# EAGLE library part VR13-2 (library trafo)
TRANSFORMER 1 primary winding, 2 secondary windings, mounting holes BLOCK

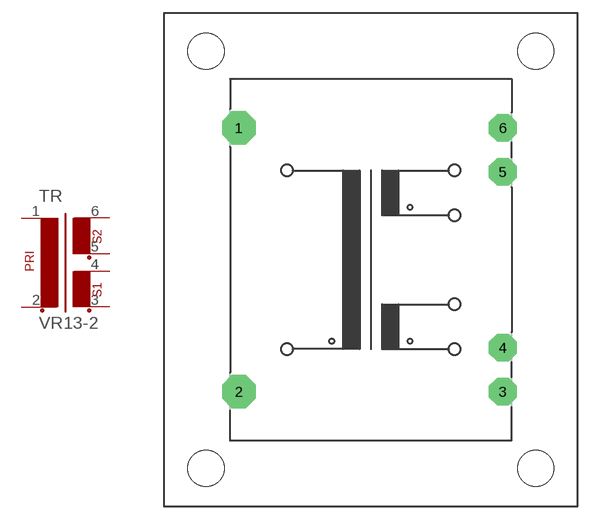
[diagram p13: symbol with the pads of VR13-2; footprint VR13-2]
Designator prefix TR

## VR13-2  [VR13-2]
1  1  pas
2  2  pas
3  3  pas
4  4  pas
5  5  pas
6  6  pas

## Footprint VR13-2 (pad centres in mm)
TRANSFORMER 1 primary winding, 2 secondary windings, mounting holes
drill 1.397 pad 3.81 octagon: 1 -15.011,15.011; 2 -15.011,-15.011
drill 1.397 pad 3.175 octagon: 3 15.011,-15.011; 4 15.011,-10.008; 5 15.011,10.008; 6 15.011,15.011
hole 4.115 at -18.745,-23.749
hole 4.115 at 18.745,-23.749
hole 4.115 at 18.745,23.749
hole 4.115 at -18.745,23.749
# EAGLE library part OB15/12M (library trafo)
TRANSFORMER 2 primary winding, 2 secondary windings with tap, mounting holes BLOCK

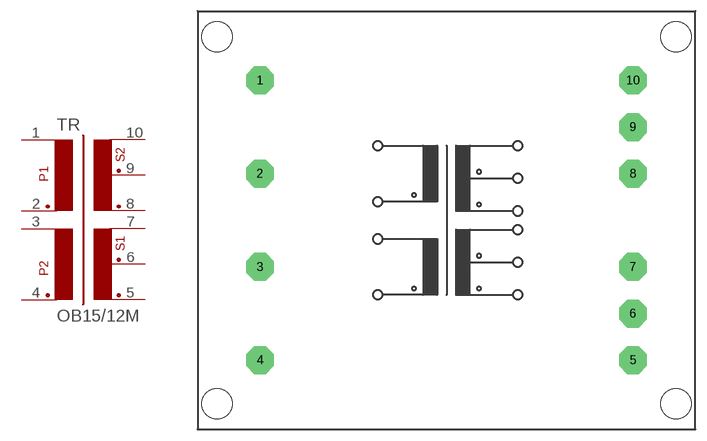
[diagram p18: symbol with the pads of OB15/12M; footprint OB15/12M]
Designator prefix TR

## OB15/12M  [OB15/12M]
1  1  pas
2  2  pas
3  3  pas
4  4  pas
5  5  pas
6  6  pas
7  7  pas
8  8  pas
9  9  pas
10  10  pas

## Footprint OB15/12M (pad centres in mm)
TRANSFORMER 2 primary winding, 2 secondary windings with tap, mounting holes
drill 1.194 pad 3.81 octagon: 1 -25.4,19.05; 2 -25.4,6.35; 3 -25.4,-6.35; 4 -25.4,-19.05; 5 25.4,-19.05; 6 25.4,-12.7; 7 25.4,-6.35; 8 25.4,6.35; 9 25.4,12.7; 10 25.4,19.05
hole 4.115 at -31.267,24.994
hole 4.115 at 31.267,24.994
hole 4.115 at 31.267,-24.994
hole 4.115 at -31.267,-24.994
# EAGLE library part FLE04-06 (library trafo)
TRANSFORMER 2 primary winding, temp. protection fuse, 2 secondary windings, mounting holes BLOCK

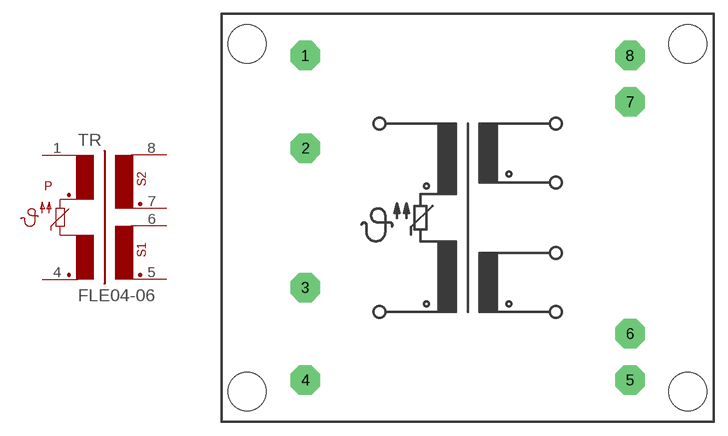
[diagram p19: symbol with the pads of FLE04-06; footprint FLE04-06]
Designator prefix TR

## FLE04-06  [FLE04-06]
1  1  pas
4  4  pas
5  5  pas
6  6  pas
7  7  pas
8  8  pas

## Footprint FLE04-06 (pad centres in mm)
TRANSFORMER 2 primary winding, 2 secondary windings, temp. protection fuse, mounting holes
drill 1.194 pad 3.175 octagon: 1 -17.501,17.501; 2 -17.501,7.518; 3 -17.501,-7.518; 4 -17.501,-17.501; 5 17.501,-17.501; 6 17.501,-12.497; 7 17.501,12.497; 8 17.501,17.501
hole 4.115 at 23.749,18.745
hole 4.115 at 23.749,-18.745
hole 4.115 at -23.774,-18.745
hole 4.115 at -23.774,18.745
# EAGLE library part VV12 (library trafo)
TRANSFORMER 1 primary winding, 2 secondary windings BLOCK

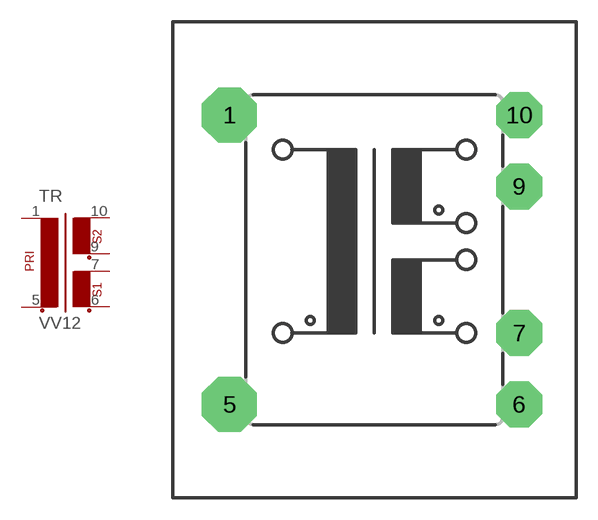
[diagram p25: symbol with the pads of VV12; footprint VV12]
Designator prefix TR

## VV12  [VV12]
1  1  pas
5  2  pas
6  3  pas
7  4  pas
9  5  pas
10  6  pas

## Footprint VV12 (pad centres in mm)
TRANSFORMER 1 primary winding, 2 secondary windings
drill 1.321 pad 3.81 octagon: 1 -10.033,10.033; 5 -10.033,-10.033
drill 1.321 pad 3.175 octagon: 6 10.033,-10.033; 7 10.033,-5.08; 9 10.033,5.08; 10 10.033,10.033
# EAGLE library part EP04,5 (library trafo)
TRANSFORMER 1 primary winding, 2 secondary windings BLOCK

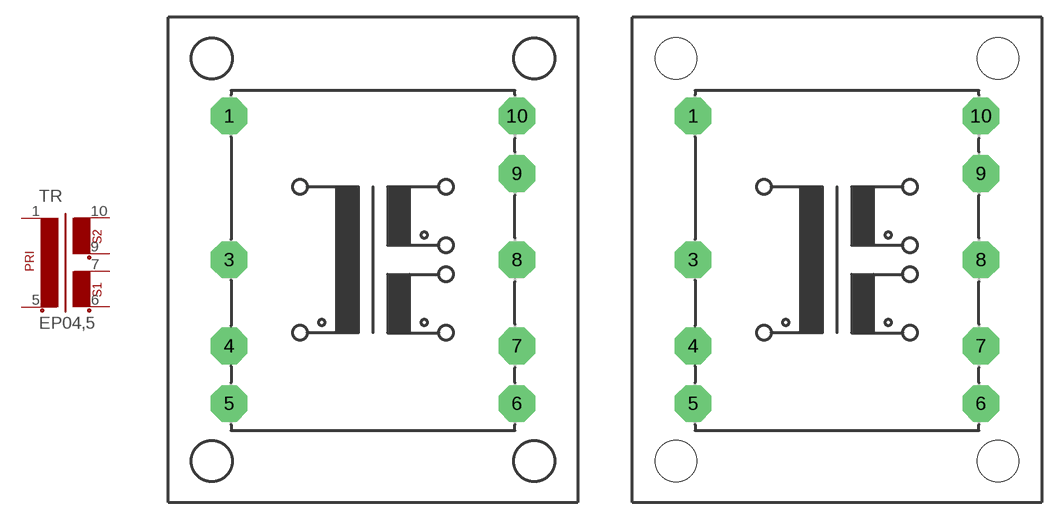
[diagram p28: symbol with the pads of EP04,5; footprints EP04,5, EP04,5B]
Designator prefix TR

## EP04,5  [EP04,5]
1  1  pas
5  2  pas
6  3  pas
7  4  pas
9  5  pas
10  6  pas

## EP04,5MH  [EP04,5B]
Pads as for EP04,5

## Footprint EP04,5 (pad centres in mm)
TRANSFORMER 1 primary winding, 2 secondary windings
drill 1.118 pad 3.175 octagon: 1 -12.497,12.497; 3 -12.497,0; 4 -12.497,-7.493; 5 -12.497,-12.497; 6 12.497,-12.497; 7 12.497,-7.493; 8 12.497,0; 9 12.497,7.493; 10 12.497,12.497

## Footprint EP04,5B (pad centres in mm)
TRANSFORMER 1 primary winding, 2 secondary windings mounting holes
drill 1.118 pad 3.175 octagon: 1 -12.497,12.497; 3 -12.497,0; 4 -12.497,-7.493; 5 -12.497,-12.497; 6 12.497,-12.497; 7 12.497,-7.493; 8 12.497,0; 9 12.497,7.493; 10 12.497,12.497
hole 3.607 at -13.995,17.501
hole 3.607 at -13.995,-17.501
hole 3.607 at 13.995,17.501
hole 3.607 at 13.995,-17.501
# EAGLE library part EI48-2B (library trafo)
TRANSFORMER 1 primary winding, 2 secondary windings, mounting holes ERA

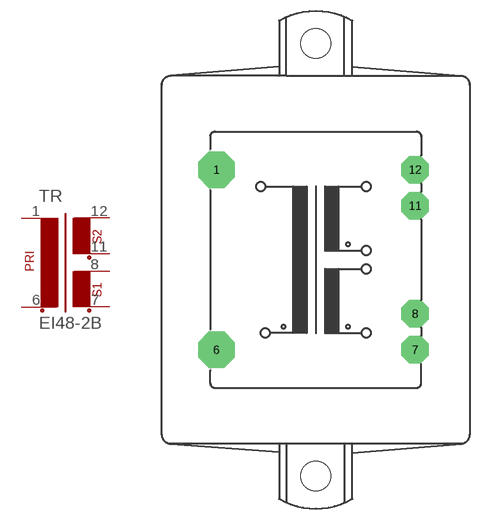
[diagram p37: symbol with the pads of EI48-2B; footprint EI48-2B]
Designator prefix TR

## EI48-2B  [EI48-2B]
1  1  pas
6  2  pas
7  3  pas
8  4  pas
11  5  pas
12  6  pas

## Footprint EI48-2B (pad centres in mm)
TRANSFORMER 1 primary winding, 2 secondary windings, mounting holes
drill 1.194 pad 5.08 octagon: 1 -13.767,12.497; 6 -13.767,-12.497
drill 1.194 pad 3.81 octagon: 7 13.767,-12.497; 8 13.767,-7.493; 11 13.767,7.493; 12 13.767,12.497
hole 4.115 at 0,-29.997
hole 4.115 at 0,29.997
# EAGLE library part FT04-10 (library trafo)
TRANSFORMER 2 primary winding, 2 secondary windings, mounting holes ERA

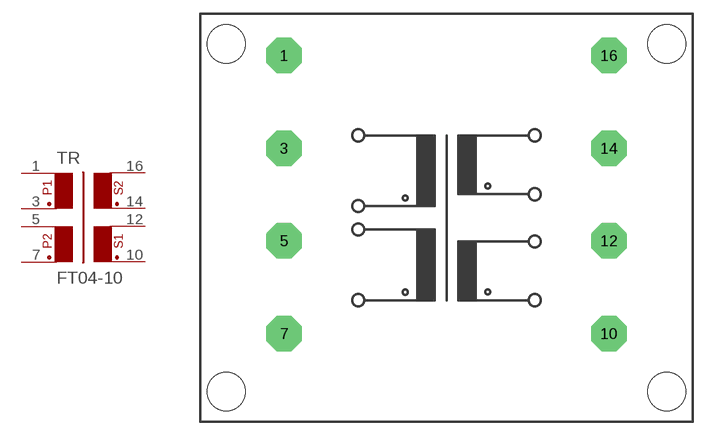
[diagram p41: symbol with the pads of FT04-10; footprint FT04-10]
Designator prefix TR

## FT04-10  [FT04-10]
1  1  pas
3  2  pas
5  3  pas
7  4  pas
10  5  pas
12  6  pas
14  7  pas
16  8  pas

## Footprint FT04-10 (pad centres in mm)
TRANSFORMER 2 primary winding, 2 secondary windings, mounting holes
drill 1.194 pad 3.81 octagon: 1 -17.501,17.501; 3 -17.501,7.493; 5 -17.501,-2.489; 7 -17.501,-12.497; 10 17.501,-12.497; 12 17.501,-2.489; 14 17.501,7.493; 16 17.501,17.501
hole 4.115 at 23.749,18.745
hole 4.115 at 23.749,-18.745
hole 4.115 at -23.749,-18.745
hole 4.115 at -23.749,18.745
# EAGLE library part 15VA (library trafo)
TRANSFORMER 1 primary windig + 1 primary winding with tap, 2 secondary windings, core ring

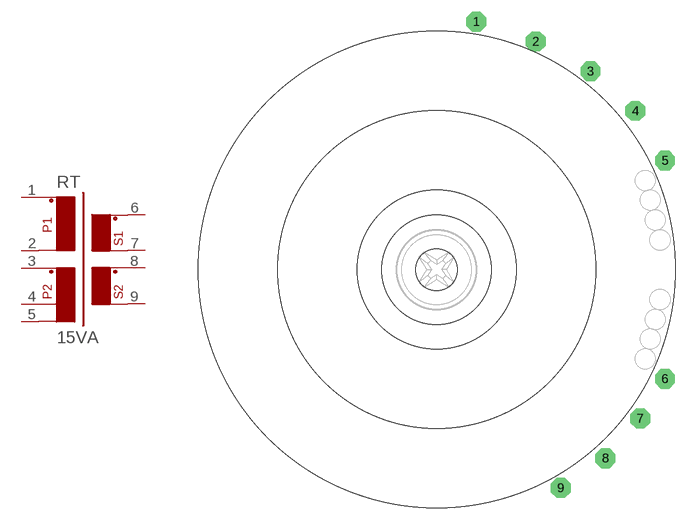
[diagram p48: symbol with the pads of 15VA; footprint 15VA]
Designator prefix RT

## 15VA  [15VA]
1  1  pas
2  2  pas
3  3  pas
4  4  pas
5  5  pas
6  6  pas
7  7  pas
8  8  pas
9  9  pas

## Footprint 15VA (pad centres in mm)
TRANSFORMER 1 primary windig + 1 primary winding with tap, 2 secondary windings, core ring
drill 1.016 pad 2.54 octagon: 1 5.08,31.75; 2 12.7,29.21; 3 19.685,25.4; 4 25.4,20.32; 5 29.21,13.97; 6 29.21,-13.97; 7 26.035,-19.05; 8 21.59,-24.13; 9 15.875,-27.94
hole 5.309 at 0,0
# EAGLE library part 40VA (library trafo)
TRANSFORMER 1 primary windig + 1 primary winding with tap, 2 secondary windings, core ring

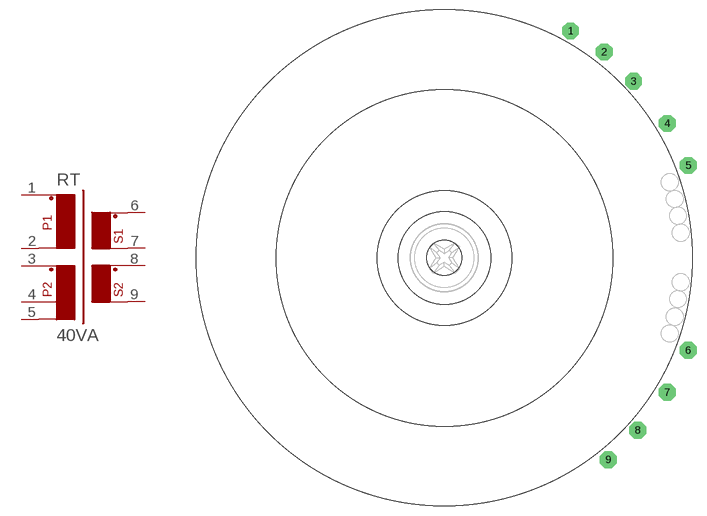
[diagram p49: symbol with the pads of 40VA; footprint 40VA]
Designator prefix RT

## 40VA  [40VA]
1  1  pas
2  2  pas
3  3  pas
4  4  pas
5  5  pas
6  6  pas
7  7  pas
8  8  pas
9  9  pas

## Footprint 40VA (pad centres in mm)
TRANSFORMER 1 primary windig + 1 primary winding with tap, 2 secondary windings, core ring
drill 1.016 pad 2.54 octagon: 1 19.05,34.29; 2 24.13,31.115; 3 28.575,26.67; 4 33.655,20.32; 5 36.83,13.97; 6 36.83,-13.97; 7 33.655,-20.32; 8 29.21,-26.035; 9 24.765,-30.48
hole 5.309 at 0,0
